VERSION 5.7 ;
  NOWIREEXTENSIONATPIN ON ;
  DIVIDERCHAR "/" ;
  BUSBITCHARS "[]" ;
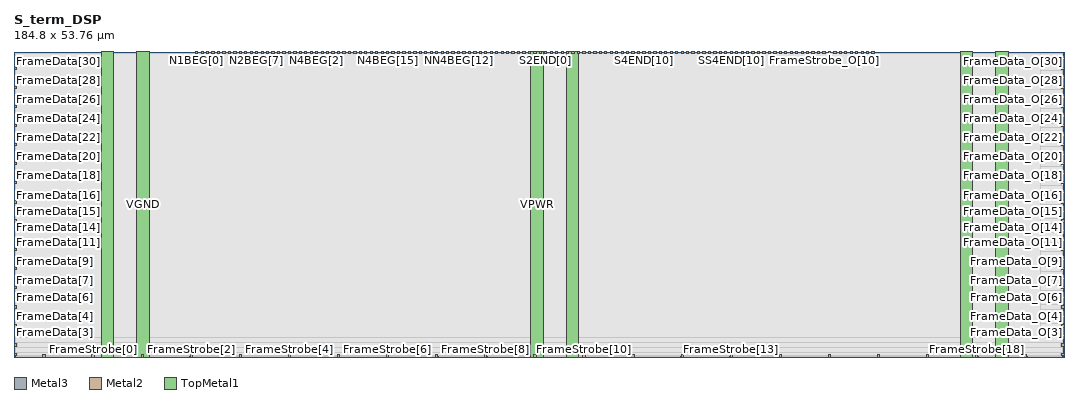
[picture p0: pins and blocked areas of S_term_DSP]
MACRO S_term_DSP
  CLASS BLOCK ;
  FOREIGN S_term_DSP ;
  ORIGIN 0.000 0.000 ;
  SIZE 184.800 BY 53.760 ;
  PIN FrameData[0]
    DIRECTION INPUT ;
    USE SIGNAL ;
    ANTENNAGATEAREA 0.180700 ;
    PORT
      LAYER Metal3 ;
        RECT 0.000 0.220 0.400 0.620 ;
    END
  END FrameData[0]
  PIN FrameData[10]
    DIRECTION INPUT ;
    USE SIGNAL ;
    ANTENNAGATEAREA 0.180700 ;
    PORT
      LAYER Metal3 ;
        RECT 0.000 17.020 0.400 17.420 ;
    END
  END FrameData[10]
  PIN FrameData[11]
    DIRECTION INPUT ;
    USE SIGNAL ;
    ANTENNAGATEAREA 0.180700 ;
    PORT
      LAYER Metal3 ;
        RECT 0.000 18.700 0.400 19.100 ;
    END
  END FrameData[11]
  PIN FrameData[12]
    DIRECTION INPUT ;
    USE SIGNAL ;
    ANTENNAGATEAREA 0.180700 ;
    PORT
      LAYER Metal3 ;
        RECT 0.000 20.380 0.400 20.780 ;
    END
  END FrameData[12]
  PIN FrameData[13]
    DIRECTION INPUT ;
    USE SIGNAL ;
    ANTENNAGATEAREA 0.180700 ;
    PORT
      LAYER Metal3 ;
        RECT 0.000 22.060 0.400 22.460 ;
    END
  END FrameData[13]
  PIN FrameData[14]
    DIRECTION INPUT ;
    USE SIGNAL ;
    ANTENNAGATEAREA 0.180700 ;
    PORT
      LAYER Metal3 ;
        RECT 0.000 23.740 0.400 24.140 ;
    END
  END FrameData[14]
  PIN FrameData[15]
    DIRECTION INPUT ;
    USE SIGNAL ;
    ANTENNAGATEAREA 0.180700 ;
    PORT
      LAYER Metal3 ;
        RECT 0.000 25.420 0.400 25.820 ;
    END
  END FrameData[15]
  PIN FrameData[16]
    DIRECTION INPUT ;
    USE SIGNAL ;
    ANTENNAGATEAREA 0.180700 ;
    PORT
      LAYER Metal3 ;
        RECT 0.000 27.100 0.400 27.500 ;
    END
  END FrameData[16]
  PIN FrameData[17]
    DIRECTION INPUT ;
    USE SIGNAL ;
    ANTENNAGATEAREA 0.180700 ;
    PORT
      LAYER Metal3 ;
        RECT 0.000 28.780 0.400 29.180 ;
    END
  END FrameData[17]
  PIN FrameData[18]
    DIRECTION INPUT ;
    USE SIGNAL ;
    ANTENNAGATEAREA 0.180700 ;
    PORT
      LAYER Metal3 ;
        RECT 0.000 30.460 0.400 30.860 ;
    END
  END FrameData[18]
  PIN FrameData[19]
    DIRECTION INPUT ;
    USE SIGNAL ;
    ANTENNAGATEAREA 0.180700 ;
    PORT
      LAYER Metal3 ;
        RECT 0.000 32.140 0.400 32.540 ;
    END
  END FrameData[19]
  PIN FrameData[1]
    DIRECTION INPUT ;
    USE SIGNAL ;
    ANTENNAGATEAREA 0.180700 ;
    PORT
      LAYER Metal3 ;
        RECT 0.000 1.900 0.400 2.300 ;
    END
  END FrameData[1]
  PIN FrameData[20]
    DIRECTION INPUT ;
    USE SIGNAL ;
    ANTENNAGATEAREA 0.180700 ;
    PORT
      LAYER Metal3 ;
        RECT 0.000 33.820 0.400 34.220 ;
    END
  END FrameData[20]
  PIN FrameData[21]
    DIRECTION INPUT ;
    USE SIGNAL ;
    ANTENNAGATEAREA 0.180700 ;
    PORT
      LAYER Metal3 ;
        RECT 0.000 35.500 0.400 35.900 ;
    END
  END FrameData[21]
  PIN FrameData[22]
    DIRECTION INPUT ;
    USE SIGNAL ;
    ANTENNAGATEAREA 0.180700 ;
    PORT
      LAYER Metal3 ;
        RECT 0.000 37.180 0.400 37.580 ;
    END
  END FrameData[22]
  PIN FrameData[23]
    DIRECTION INPUT ;
    USE SIGNAL ;
    ANTENNAGATEAREA 0.180700 ;
    PORT
      LAYER Metal3 ;
        RECT 0.000 38.860 0.400 39.260 ;
    END
  END FrameData[23]
  PIN FrameData[24]
    DIRECTION INPUT ;
    USE SIGNAL ;
    ANTENNAGATEAREA 0.180700 ;
    PORT
      LAYER Metal3 ;
        RECT 0.000 40.540 0.400 40.940 ;
    END
  END FrameData[24]
  PIN FrameData[25]
    DIRECTION INPUT ;
    USE SIGNAL ;
    ANTENNAGATEAREA 0.180700 ;
    PORT
      LAYER Metal3 ;
        RECT 0.000 42.220 0.400 42.620 ;
    END
  END FrameData[25]
  PIN FrameData[26]
    DIRECTION INPUT ;
    USE SIGNAL ;
    ANTENNAGATEAREA 0.180700 ;
    PORT
      LAYER Metal3 ;
        RECT 0.000 43.900 0.400 44.300 ;
    END
  END FrameData[26]
  PIN FrameData[27]
    DIRECTION INPUT ;
    USE SIGNAL ;
    ANTENNAGATEAREA 0.180700 ;
    PORT
      LAYER Metal3 ;
        RECT 0.000 45.580 0.400 45.980 ;
    END
  END FrameData[27]
  PIN FrameData[28]
    DIRECTION INPUT ;
    USE SIGNAL ;
    ANTENNAGATEAREA 0.180700 ;
    PORT
      LAYER Metal3 ;
        RECT 0.000 47.260 0.400 47.660 ;
    END
  END FrameData[28]
  PIN FrameData[29]
    DIRECTION INPUT ;
    USE SIGNAL ;
    ANTENNAGATEAREA 0.180700 ;
    PORT
      LAYER Metal3 ;
        RECT 0.000 48.940 0.400 49.340 ;
    END
  END FrameData[29]
  PIN FrameData[2]
    DIRECTION INPUT ;
    USE SIGNAL ;
    ANTENNAGATEAREA 0.180700 ;
    PORT
      LAYER Metal3 ;
        RECT 0.000 3.580 0.400 3.980 ;
    END
  END FrameData[2]
  PIN FrameData[30]
    DIRECTION INPUT ;
    USE SIGNAL ;
    ANTENNAGATEAREA 0.180700 ;
    PORT
      LAYER Metal3 ;
        RECT 0.000 50.620 0.400 51.020 ;
    END
  END FrameData[30]
  PIN FrameData[31]
    DIRECTION INPUT ;
    USE SIGNAL ;
    ANTENNAGATEAREA 0.180700 ;
    PORT
      LAYER Metal3 ;
        RECT 0.000 52.300 0.400 52.700 ;
    END
  END FrameData[31]
  PIN FrameData[3]
    DIRECTION INPUT ;
    USE SIGNAL ;
    ANTENNAGATEAREA 0.180700 ;
    PORT
      LAYER Metal3 ;
        RECT 0.000 5.260 0.400 5.660 ;
    END
  END FrameData[3]
  PIN FrameData[4]
    DIRECTION INPUT ;
    USE SIGNAL ;
    ANTENNAGATEAREA 0.180700 ;
    PORT
      LAYER Metal3 ;
        RECT 0.000 6.940 0.400 7.340 ;
    END
  END FrameData[4]
  PIN FrameData[5]
    DIRECTION INPUT ;
    USE SIGNAL ;
    ANTENNAGATEAREA 0.180700 ;
    PORT
      LAYER Metal3 ;
        RECT 0.000 8.620 0.400 9.020 ;
    END
  END FrameData[5]
  PIN FrameData[6]
    DIRECTION INPUT ;
    USE SIGNAL ;
    ANTENNAGATEAREA 0.180700 ;
    PORT
      LAYER Metal3 ;
        RECT 0.000 10.300 0.400 10.700 ;
    END
  END FrameData[6]
  PIN FrameData[7]
    DIRECTION INPUT ;
    USE SIGNAL ;
    ANTENNAGATEAREA 0.180700 ;
    PORT
      LAYER Metal3 ;
        RECT 0.000 11.980 0.400 12.380 ;
    END
  END FrameData[7]
  PIN FrameData[8]
    DIRECTION INPUT ;
    USE SIGNAL ;
    ANTENNAGATEAREA 0.180700 ;
    PORT
      LAYER Metal3 ;
        RECT 0.000 13.660 0.400 14.060 ;
    END
  END FrameData[8]
  PIN FrameData[9]
    DIRECTION INPUT ;
    USE SIGNAL ;
    ANTENNAGATEAREA 0.180700 ;
    PORT
      LAYER Metal3 ;
        RECT 0.000 15.340 0.400 15.740 ;
    END
  END FrameData[9]
  PIN FrameData_O[0]
    DIRECTION OUTPUT ;
    USE SIGNAL ;
    ANTENNADIFFAREA 0.708600 ;
    PORT
      LAYER Metal3 ;
        RECT 184.400 0.220 184.800 0.620 ;
    END
  END FrameData_O[0]
  PIN FrameData_O[10]
    DIRECTION OUTPUT ;
    USE SIGNAL ;
    ANTENNADIFFAREA 0.708600 ;
    PORT
      LAYER Metal3 ;
        RECT 184.400 17.020 184.800 17.420 ;
    END
  END FrameData_O[10]
  PIN FrameData_O[11]
    DIRECTION OUTPUT ;
    USE SIGNAL ;
    ANTENNADIFFAREA 0.708600 ;
    PORT
      LAYER Metal3 ;
        RECT 184.400 18.700 184.800 19.100 ;
    END
  END FrameData_O[11]
  PIN FrameData_O[12]
    DIRECTION OUTPUT ;
    USE SIGNAL ;
    ANTENNADIFFAREA 0.708600 ;
    PORT
      LAYER Metal3 ;
        RECT 184.400 20.380 184.800 20.780 ;
    END
  END FrameData_O[12]
  PIN FrameData_O[13]
    DIRECTION OUTPUT ;
    USE SIGNAL ;
    ANTENNADIFFAREA 0.708600 ;
    PORT
      LAYER Metal3 ;
        RECT 184.400 22.060 184.800 22.460 ;
    END
  END FrameData_O[13]
  PIN FrameData_O[14]
    DIRECTION OUTPUT ;
    USE SIGNAL ;
    ANTENNADIFFAREA 0.708600 ;
    PORT
      LAYER Metal3 ;
        RECT 184.400 23.740 184.800 24.140 ;
    END
  END FrameData_O[14]
  PIN FrameData_O[15]
    DIRECTION OUTPUT ;
    USE SIGNAL ;
    ANTENNADIFFAREA 0.708600 ;
    PORT
      LAYER Metal3 ;
        RECT 184.400 25.420 184.800 25.820 ;
    END
  END FrameData_O[15]
  PIN FrameData_O[16]
    DIRECTION OUTPUT ;
    USE SIGNAL ;
    ANTENNADIFFAREA 0.708600 ;
    PORT
      LAYER Metal3 ;
        RECT 184.400 27.100 184.800 27.500 ;
    END
  END FrameData_O[16]
  PIN FrameData_O[17]
    DIRECTION OUTPUT ;
    USE SIGNAL ;
    ANTENNADIFFAREA 0.708600 ;
    PORT
      LAYER Metal3 ;
        RECT 184.400 28.780 184.800 29.180 ;
    END
  END FrameData_O[17]
  PIN FrameData_O[18]
    DIRECTION OUTPUT ;
    USE SIGNAL ;
    ANTENNADIFFAREA 0.708600 ;
    PORT
      LAYER Metal3 ;
        RECT 184.400 30.460 184.800 30.860 ;
    END
  END FrameData_O[18]
  PIN FrameData_O[19]
    DIRECTION OUTPUT ;
    USE SIGNAL ;
    ANTENNADIFFAREA 0.708600 ;
    PORT
      LAYER Metal3 ;
        RECT 184.400 32.140 184.800 32.540 ;
    END
  END FrameData_O[19]
  PIN FrameData_O[1]
    DIRECTION OUTPUT ;
    USE SIGNAL ;
    ANTENNADIFFAREA 0.708600 ;
    PORT
      LAYER Metal3 ;
        RECT 184.400 1.900 184.800 2.300 ;
    END
  END FrameData_O[1]
  PIN FrameData_O[20]
    DIRECTION OUTPUT ;
    USE SIGNAL ;
    ANTENNADIFFAREA 0.708600 ;
    PORT
      LAYER Metal3 ;
        RECT 184.400 33.820 184.800 34.220 ;
    END
  END FrameData_O[20]
  PIN FrameData_O[21]
    DIRECTION OUTPUT ;
    USE SIGNAL ;
    ANTENNADIFFAREA 0.708600 ;
    PORT
      LAYER Metal3 ;
        RECT 184.400 35.500 184.800 35.900 ;
    END
  END FrameData_O[21]
  PIN FrameData_O[22]
    DIRECTION OUTPUT ;
    USE SIGNAL ;
    ANTENNADIFFAREA 0.708600 ;
    PORT
      LAYER Metal3 ;
        RECT 184.400 37.180 184.800 37.580 ;
    END
  END FrameData_O[22]
  PIN FrameData_O[23]
    DIRECTION OUTPUT ;
    USE SIGNAL ;
    ANTENNADIFFAREA 0.708600 ;
    PORT
      LAYER Metal3 ;
        RECT 184.400 38.860 184.800 39.260 ;
    END
  END FrameData_O[23]
  PIN FrameData_O[24]
    DIRECTION OUTPUT ;
    USE SIGNAL ;
    ANTENNADIFFAREA 0.708600 ;
    PORT
      LAYER Metal3 ;
        RECT 184.400 40.540 184.800 40.940 ;
    END
  END FrameData_O[24]
  PIN FrameData_O[25]
    DIRECTION OUTPUT ;
    USE SIGNAL ;
    ANTENNADIFFAREA 0.708600 ;
    PORT
      LAYER Metal3 ;
        RECT 184.400 42.220 184.800 42.620 ;
    END
  END FrameData_O[25]
  PIN FrameData_O[26]
    DIRECTION OUTPUT ;
    USE SIGNAL ;
    ANTENNADIFFAREA 0.708600 ;
    PORT
      LAYER Metal3 ;
        RECT 184.400 43.900 184.800 44.300 ;
    END
  END FrameData_O[26]
  PIN FrameData_O[27]
    DIRECTION OUTPUT ;
    USE SIGNAL ;
    ANTENNADIFFAREA 0.708600 ;
    PORT
      LAYER Metal3 ;
        RECT 184.400 45.580 184.800 45.980 ;
    END
  END FrameData_O[27]
  PIN FrameData_O[28]
    DIRECTION OUTPUT ;
    USE SIGNAL ;
    ANTENNADIFFAREA 0.708600 ;
    PORT
      LAYER Metal3 ;
        RECT 184.400 47.260 184.800 47.660 ;
    END
  END FrameData_O[28]
  PIN FrameData_O[29]
    DIRECTION OUTPUT ;
    USE SIGNAL ;
    ANTENNADIFFAREA 0.708600 ;
    PORT
      LAYER Metal3 ;
        RECT 184.400 48.940 184.800 49.340 ;
    END
  END FrameData_O[29]
  PIN FrameData_O[2]
    DIRECTION OUTPUT ;
    USE SIGNAL ;
    ANTENNADIFFAREA 0.708600 ;
    PORT
      LAYER Metal3 ;
        RECT 184.400 3.580 184.800 3.980 ;
    END
  END FrameData_O[2]
  PIN FrameData_O[30]
    DIRECTION OUTPUT ;
    USE SIGNAL ;
    ANTENNADIFFAREA 0.708600 ;
    PORT
      LAYER Metal3 ;
        RECT 184.400 50.620 184.800 51.020 ;
    END
  END FrameData_O[30]
  PIN FrameData_O[31]
    DIRECTION OUTPUT ;
    USE SIGNAL ;
    ANTENNADIFFAREA 0.708600 ;
    PORT
      LAYER Metal3 ;
        RECT 184.400 52.300 184.800 52.700 ;
    END
  END FrameData_O[31]
  PIN FrameData_O[3]
    DIRECTION OUTPUT ;
    USE SIGNAL ;
    ANTENNADIFFAREA 0.708600 ;
    PORT
      LAYER Metal3 ;
        RECT 184.400 5.260 184.800 5.660 ;
    END
  END FrameData_O[3]
  PIN FrameData_O[4]
    DIRECTION OUTPUT ;
    USE SIGNAL ;
    ANTENNADIFFAREA 0.708600 ;
    PORT
      LAYER Metal3 ;
        RECT 184.400 6.940 184.800 7.340 ;
    END
  END FrameData_O[4]
  PIN FrameData_O[5]
    DIRECTION OUTPUT ;
    USE SIGNAL ;
    ANTENNADIFFAREA 0.708600 ;
    PORT
      LAYER Metal3 ;
        RECT 184.400 8.620 184.800 9.020 ;
    END
  END FrameData_O[5]
  PIN FrameData_O[6]
    DIRECTION OUTPUT ;
    USE SIGNAL ;
    ANTENNADIFFAREA 0.708600 ;
    PORT
      LAYER Metal3 ;
        RECT 184.400 10.300 184.800 10.700 ;
    END
  END FrameData_O[6]
  PIN FrameData_O[7]
    DIRECTION OUTPUT ;
    USE SIGNAL ;
    ANTENNADIFFAREA 0.708600 ;
    PORT
      LAYER Metal3 ;
        RECT 184.400 11.980 184.800 12.380 ;
    END
  END FrameData_O[7]
  PIN FrameData_O[8]
    DIRECTION OUTPUT ;
    USE SIGNAL ;
    ANTENNADIFFAREA 0.708600 ;
    PORT
      LAYER Metal3 ;
        RECT 184.400 13.660 184.800 14.060 ;
    END
  END FrameData_O[8]
  PIN FrameData_O[9]
    DIRECTION OUTPUT ;
    USE SIGNAL ;
    ANTENNADIFFAREA 0.708600 ;
    PORT
      LAYER Metal3 ;
        RECT 184.400 15.340 184.800 15.740 ;
    END
  END FrameData_O[9]
  PIN FrameStrobe[0]
    DIRECTION INPUT ;
    USE SIGNAL ;
    ANTENNAGATEAREA 0.180700 ;
    PORT
      LAYER Metal2 ;
        RECT 13.720 0.000 14.120 0.400 ;
    END
  END FrameStrobe[0]
  PIN FrameStrobe[10]
    DIRECTION INPUT ;
    USE SIGNAL ;
    ANTENNAGATEAREA 0.180700 ;
    PORT
      LAYER Metal2 ;
        RECT 100.120 0.000 100.520 0.400 ;
    END
  END FrameStrobe[10]
  PIN FrameStrobe[11]
    DIRECTION INPUT ;
    USE SIGNAL ;
    ANTENNAGATEAREA 0.180700 ;
    PORT
      LAYER Metal2 ;
        RECT 108.760 0.000 109.160 0.400 ;
    END
  END FrameStrobe[11]
  PIN FrameStrobe[12]
    DIRECTION INPUT ;
    USE SIGNAL ;
    ANTENNAGATEAREA 0.180700 ;
    PORT
      LAYER Metal2 ;
        RECT 117.400 0.000 117.800 0.400 ;
    END
  END FrameStrobe[12]
  PIN FrameStrobe[13]
    DIRECTION INPUT ;
    USE SIGNAL ;
    ANTENNAGATEAREA 0.180700 ;
    PORT
      LAYER Metal2 ;
        RECT 126.040 0.000 126.440 0.400 ;
    END
  END FrameStrobe[13]
  PIN FrameStrobe[14]
    DIRECTION INPUT ;
    USE SIGNAL ;
    ANTENNAGATEAREA 0.180700 ;
    PORT
      LAYER Metal2 ;
        RECT 134.680 0.000 135.080 0.400 ;
    END
  END FrameStrobe[14]
  PIN FrameStrobe[15]
    DIRECTION INPUT ;
    USE SIGNAL ;
    ANTENNAGATEAREA 0.180700 ;
    PORT
      LAYER Metal2 ;
        RECT 143.320 0.000 143.720 0.400 ;
    END
  END FrameStrobe[15]
  PIN FrameStrobe[16]
    DIRECTION INPUT ;
    USE SIGNAL ;
    ANTENNAGATEAREA 0.180700 ;
    PORT
      LAYER Metal2 ;
        RECT 151.960 0.000 152.360 0.400 ;
    END
  END FrameStrobe[16]
  PIN FrameStrobe[17]
    DIRECTION INPUT ;
    USE SIGNAL ;
    ANTENNAGATEAREA 0.180700 ;
    PORT
      LAYER Metal2 ;
        RECT 160.600 0.000 161.000 0.400 ;
    END
  END FrameStrobe[17]
  PIN FrameStrobe[18]
    DIRECTION INPUT ;
    USE SIGNAL ;
    ANTENNAGATEAREA 0.180700 ;
    PORT
      LAYER Metal2 ;
        RECT 169.240 0.000 169.640 0.400 ;
    END
  END FrameStrobe[18]
  PIN FrameStrobe[19]
    DIRECTION INPUT ;
    USE SIGNAL ;
    ANTENNAGATEAREA 0.180700 ;
    PORT
      LAYER Metal2 ;
        RECT 177.880 0.000 178.280 0.400 ;
    END
  END FrameStrobe[19]
  PIN FrameStrobe[1]
    DIRECTION INPUT ;
    USE SIGNAL ;
    ANTENNAGATEAREA 0.180700 ;
    PORT
      LAYER Metal2 ;
        RECT 22.360 0.000 22.760 0.400 ;
    END
  END FrameStrobe[1]
  PIN FrameStrobe[2]
    DIRECTION INPUT ;
    USE SIGNAL ;
    ANTENNAGATEAREA 0.180700 ;
    PORT
      LAYER Metal2 ;
        RECT 31.000 0.000 31.400 0.400 ;
    END
  END FrameStrobe[2]
  PIN FrameStrobe[3]
    DIRECTION INPUT ;
    USE SIGNAL ;
    ANTENNAGATEAREA 0.180700 ;
    PORT
      LAYER Metal2 ;
        RECT 39.640 0.000 40.040 0.400 ;
    END
  END FrameStrobe[3]
  PIN FrameStrobe[4]
    DIRECTION INPUT ;
    USE SIGNAL ;
    ANTENNAGATEAREA 0.180700 ;
    PORT
      LAYER Metal2 ;
        RECT 48.280 0.000 48.680 0.400 ;
    END
  END FrameStrobe[4]
  PIN FrameStrobe[5]
    DIRECTION INPUT ;
    USE SIGNAL ;
    ANTENNAGATEAREA 0.180700 ;
    PORT
      LAYER Metal2 ;
        RECT 56.920 0.000 57.320 0.400 ;
    END
  END FrameStrobe[5]
  PIN FrameStrobe[6]
    DIRECTION INPUT ;
    USE SIGNAL ;
    ANTENNAGATEAREA 0.180700 ;
    PORT
      LAYER Metal2 ;
        RECT 65.560 0.000 65.960 0.400 ;
    END
  END FrameStrobe[6]
  PIN FrameStrobe[7]
    DIRECTION INPUT ;
    USE SIGNAL ;
    ANTENNAGATEAREA 0.180700 ;
    PORT
      LAYER Metal2 ;
        RECT 74.200 0.000 74.600 0.400 ;
    END
  END FrameStrobe[7]
  PIN FrameStrobe[8]
    DIRECTION INPUT ;
    USE SIGNAL ;
    ANTENNAGATEAREA 0.180700 ;
    PORT
      LAYER Metal2 ;
        RECT 82.840 0.000 83.240 0.400 ;
    END
  END FrameStrobe[8]
  PIN FrameStrobe[9]
    DIRECTION INPUT ;
    USE SIGNAL ;
    ANTENNAGATEAREA 0.180700 ;
    PORT
      LAYER Metal2 ;
        RECT 91.480 0.000 91.880 0.400 ;
    END
  END FrameStrobe[9]
  PIN FrameStrobe_O[0]
    DIRECTION OUTPUT ;
    USE SIGNAL ;
    ANTENNADIFFAREA 0.708600 ;
    PORT
      LAYER Metal2 ;
        RECT 132.760 53.360 133.160 53.760 ;
    END
  END FrameStrobe_O[0]
  PIN FrameStrobe_O[10]
    DIRECTION OUTPUT ;
    USE SIGNAL ;
    ANTENNADIFFAREA 0.708600 ;
    PORT
      LAYER Metal2 ;
        RECT 142.360 53.360 142.760 53.760 ;
    END
  END FrameStrobe_O[10]
  PIN FrameStrobe_O[11]
    DIRECTION OUTPUT ;
    USE SIGNAL ;
    ANTENNADIFFAREA 0.708600 ;
    PORT
      LAYER Metal2 ;
        RECT 143.320 53.360 143.720 53.760 ;
    END
  END FrameStrobe_O[11]
  PIN FrameStrobe_O[12]
    DIRECTION OUTPUT ;
    USE SIGNAL ;
    ANTENNADIFFAREA 0.708600 ;
    PORT
      LAYER Metal2 ;
        RECT 144.280 53.360 144.680 53.760 ;
    END
  END FrameStrobe_O[12]
  PIN FrameStrobe_O[13]
    DIRECTION OUTPUT ;
    USE SIGNAL ;
    ANTENNADIFFAREA 0.708600 ;
    PORT
      LAYER Metal2 ;
        RECT 145.240 53.360 145.640 53.760 ;
    END
  END FrameStrobe_O[13]
  PIN FrameStrobe_O[14]
    DIRECTION OUTPUT ;
    USE SIGNAL ;
    ANTENNADIFFAREA 0.708600 ;
    PORT
      LAYER Metal2 ;
        RECT 146.200 53.360 146.600 53.760 ;
    END
  END FrameStrobe_O[14]
  PIN FrameStrobe_O[15]
    DIRECTION OUTPUT ;
    USE SIGNAL ;
    ANTENNADIFFAREA 0.708600 ;
    PORT
      LAYER Metal2 ;
        RECT 147.160 53.360 147.560 53.760 ;
    END
  END FrameStrobe_O[15]
  PIN FrameStrobe_O[16]
    DIRECTION OUTPUT ;
    USE SIGNAL ;
    ANTENNADIFFAREA 0.708600 ;
    PORT
      LAYER Metal2 ;
        RECT 148.120 53.360 148.520 53.760 ;
    END
  END FrameStrobe_O[16]
  PIN FrameStrobe_O[17]
    DIRECTION OUTPUT ;
    USE SIGNAL ;
    ANTENNADIFFAREA 0.708600 ;
    PORT
      LAYER Metal2 ;
        RECT 149.080 53.360 149.480 53.760 ;
    END
  END FrameStrobe_O[17]
  PIN FrameStrobe_O[18]
    DIRECTION OUTPUT ;
    USE SIGNAL ;
    ANTENNADIFFAREA 0.708600 ;
    PORT
      LAYER Metal2 ;
        RECT 150.040 53.360 150.440 53.760 ;
    END
  END FrameStrobe_O[18]
  PIN FrameStrobe_O[19]
    DIRECTION OUTPUT ;
    USE SIGNAL ;
    ANTENNADIFFAREA 0.708600 ;
    PORT
      LAYER Metal2 ;
        RECT 151.000 53.360 151.400 53.760 ;
    END
  END FrameStrobe_O[19]
  PIN FrameStrobe_O[1]
    DIRECTION OUTPUT ;
    USE SIGNAL ;
    ANTENNADIFFAREA 0.708600 ;
    PORT
      LAYER Metal2 ;
        RECT 133.720 53.360 134.120 53.760 ;
    END
  END FrameStrobe_O[1]
  PIN FrameStrobe_O[2]
    DIRECTION OUTPUT ;
    USE SIGNAL ;
    ANTENNADIFFAREA 0.708600 ;
    PORT
      LAYER Metal2 ;
        RECT 134.680 53.360 135.080 53.760 ;
    END
  END FrameStrobe_O[2]
  PIN FrameStrobe_O[3]
    DIRECTION OUTPUT ;
    USE SIGNAL ;
    ANTENNADIFFAREA 0.708600 ;
    PORT
      LAYER Metal2 ;
        RECT 135.640 53.360 136.040 53.760 ;
    END
  END FrameStrobe_O[3]
  PIN FrameStrobe_O[4]
    DIRECTION OUTPUT ;
    USE SIGNAL ;
    ANTENNADIFFAREA 0.708600 ;
    PORT
      LAYER Metal2 ;
        RECT 136.600 53.360 137.000 53.760 ;
    END
  END FrameStrobe_O[4]
  PIN FrameStrobe_O[5]
    DIRECTION OUTPUT ;
    USE SIGNAL ;
    ANTENNADIFFAREA 0.708600 ;
    PORT
      LAYER Metal2 ;
        RECT 137.560 53.360 137.960 53.760 ;
    END
  END FrameStrobe_O[5]
  PIN FrameStrobe_O[6]
    DIRECTION OUTPUT ;
    USE SIGNAL ;
    ANTENNADIFFAREA 0.708600 ;
    PORT
      LAYER Metal2 ;
        RECT 138.520 53.360 138.920 53.760 ;
    END
  END FrameStrobe_O[6]
  PIN FrameStrobe_O[7]
    DIRECTION OUTPUT ;
    USE SIGNAL ;
    ANTENNADIFFAREA 0.708600 ;
    PORT
      LAYER Metal2 ;
        RECT 139.480 53.360 139.880 53.760 ;
    END
  END FrameStrobe_O[7]
  PIN FrameStrobe_O[8]
    DIRECTION OUTPUT ;
    USE SIGNAL ;
    ANTENNADIFFAREA 0.708600 ;
    PORT
      LAYER Metal2 ;
        RECT 140.440 53.360 140.840 53.760 ;
    END
  END FrameStrobe_O[8]
  PIN FrameStrobe_O[9]
    DIRECTION OUTPUT ;
    USE SIGNAL ;
    ANTENNADIFFAREA 0.708600 ;
    PORT
      LAYER Metal2 ;
        RECT 141.400 53.360 141.800 53.760 ;
    END
  END FrameStrobe_O[9]
  PIN N1BEG[0]
    DIRECTION OUTPUT ;
    USE SIGNAL ;
    ANTENNADIFFAREA 0.708600 ;
    PORT
      LAYER Metal2 ;
        RECT 31.960 53.360 32.360 53.760 ;
    END
  END N1BEG[0]
  PIN N1BEG[1]
    DIRECTION OUTPUT ;
    USE SIGNAL ;
    ANTENNADIFFAREA 0.708600 ;
    PORT
      LAYER Metal2 ;
        RECT 32.920 53.360 33.320 53.760 ;
    END
  END N1BEG[1]
  PIN N1BEG[2]
    DIRECTION OUTPUT ;
    USE SIGNAL ;
    ANTENNADIFFAREA 0.708600 ;
    PORT
      LAYER Metal2 ;
        RECT 33.880 53.360 34.280 53.760 ;
    END
  END N1BEG[2]
  PIN N1BEG[3]
    DIRECTION OUTPUT ;
    USE SIGNAL ;
    ANTENNADIFFAREA 0.708600 ;
    PORT
      LAYER Metal2 ;
        RECT 34.840 53.360 35.240 53.760 ;
    END
  END N1BEG[3]
  PIN N2BEG[0]
    DIRECTION OUTPUT ;
    USE SIGNAL ;
    ANTENNADIFFAREA 0.708600 ;
    PORT
      LAYER Metal2 ;
        RECT 35.800 53.360 36.200 53.760 ;
    END
  END N2BEG[0]
  PIN N2BEG[1]
    DIRECTION OUTPUT ;
    USE SIGNAL ;
    ANTENNADIFFAREA 0.708600 ;
    PORT
      LAYER Metal2 ;
        RECT 36.760 53.360 37.160 53.760 ;
    END
  END N2BEG[1]
  PIN N2BEG[2]
    DIRECTION OUTPUT ;
    USE SIGNAL ;
    ANTENNADIFFAREA 0.708600 ;
    PORT
      LAYER Metal2 ;
        RECT 37.720 53.360 38.120 53.760 ;
    END
  END N2BEG[2]
  PIN N2BEG[3]
    DIRECTION OUTPUT ;
    USE SIGNAL ;
    ANTENNADIFFAREA 0.708600 ;
    PORT
      LAYER Metal2 ;
        RECT 38.680 53.360 39.080 53.760 ;
    END
  END N2BEG[3]
  PIN N2BEG[4]
    DIRECTION OUTPUT ;
    USE SIGNAL ;
    ANTENNADIFFAREA 0.708600 ;
    PORT
      LAYER Metal2 ;
        RECT 39.640 53.360 40.040 53.760 ;
    END
  END N2BEG[4]
  PIN N2BEG[5]
    DIRECTION OUTPUT ;
    USE SIGNAL ;
    ANTENNADIFFAREA 0.708600 ;
    PORT
      LAYER Metal2 ;
        RECT 40.600 53.360 41.000 53.760 ;
    END
  END N2BEG[5]
  PIN N2BEG[6]
    DIRECTION OUTPUT ;
    USE SIGNAL ;
    ANTENNADIFFAREA 0.708600 ;
    PORT
      LAYER Metal2 ;
        RECT 41.560 53.360 41.960 53.760 ;
    END
  END N2BEG[6]
  PIN N2BEG[7]
    DIRECTION OUTPUT ;
    USE SIGNAL ;
    ANTENNADIFFAREA 0.708600 ;
    PORT
      LAYER Metal2 ;
        RECT 42.520 53.360 42.920 53.760 ;
    END
  END N2BEG[7]
  PIN N2BEGb[0]
    DIRECTION OUTPUT ;
    USE SIGNAL ;
    ANTENNADIFFAREA 0.708600 ;
    PORT
      LAYER Metal2 ;
        RECT 43.480 53.360 43.880 53.760 ;
    END
  END N2BEGb[0]
  PIN N2BEGb[1]
    DIRECTION OUTPUT ;
    USE SIGNAL ;
    ANTENNADIFFAREA 0.708600 ;
    PORT
      LAYER Metal2 ;
        RECT 44.440 53.360 44.840 53.760 ;
    END
  END N2BEGb[1]
  PIN N2BEGb[2]
    DIRECTION OUTPUT ;
    USE SIGNAL ;
    ANTENNADIFFAREA 0.708600 ;
    PORT
      LAYER Metal2 ;
        RECT 45.400 53.360 45.800 53.760 ;
    END
  END N2BEGb[2]
  PIN N2BEGb[3]
    DIRECTION OUTPUT ;
    USE SIGNAL ;
    ANTENNADIFFAREA 0.708600 ;
    PORT
      LAYER Metal2 ;
        RECT 46.360 53.360 46.760 53.760 ;
    END
  END N2BEGb[3]
  PIN N2BEGb[4]
    DIRECTION OUTPUT ;
    USE SIGNAL ;
    ANTENNADIFFAREA 0.708600 ;
    PORT
      LAYER Metal2 ;
        RECT 47.320 53.360 47.720 53.760 ;
    END
  END N2BEGb[4]
  PIN N2BEGb[5]
    DIRECTION OUTPUT ;
    USE SIGNAL ;
    ANTENNADIFFAREA 0.708600 ;
    PORT
      LAYER Metal2 ;
        RECT 48.280 53.360 48.680 53.760 ;
    END
  END N2BEGb[5]
  PIN N2BEGb[6]
    DIRECTION OUTPUT ;
    USE SIGNAL ;
    ANTENNADIFFAREA 0.708600 ;
    PORT
      LAYER Metal2 ;
        RECT 49.240 53.360 49.640 53.760 ;
    END
  END N2BEGb[6]
  PIN N2BEGb[7]
    DIRECTION OUTPUT ;
    USE SIGNAL ;
    ANTENNADIFFAREA 0.708600 ;
    PORT
      LAYER Metal2 ;
        RECT 50.200 53.360 50.600 53.760 ;
    END
  END N2BEGb[7]
  PIN N4BEG[0]
    DIRECTION OUTPUT ;
    USE SIGNAL ;
    ANTENNADIFFAREA 0.708600 ;
    PORT
      LAYER Metal2 ;
        RECT 51.160 53.360 51.560 53.760 ;
    END
  END N4BEG[0]
  PIN N4BEG[10]
    DIRECTION OUTPUT ;
    USE SIGNAL ;
    ANTENNADIFFAREA 0.708600 ;
    PORT
      LAYER Metal2 ;
        RECT 60.760 53.360 61.160 53.760 ;
    END
  END N4BEG[10]
  PIN N4BEG[11]
    DIRECTION OUTPUT ;
    USE SIGNAL ;
    ANTENNADIFFAREA 0.708600 ;
    PORT
      LAYER Metal2 ;
        RECT 61.720 53.360 62.120 53.760 ;
    END
  END N4BEG[11]
  PIN N4BEG[12]
    DIRECTION OUTPUT ;
    USE SIGNAL ;
    ANTENNADIFFAREA 0.708600 ;
    PORT
      LAYER Metal2 ;
        RECT 62.680 53.360 63.080 53.760 ;
    END
  END N4BEG[12]
  PIN N4BEG[13]
    DIRECTION OUTPUT ;
    USE SIGNAL ;
    ANTENNADIFFAREA 0.708600 ;
    PORT
      LAYER Metal2 ;
        RECT 63.640 53.360 64.040 53.760 ;
    END
  END N4BEG[13]
  PIN N4BEG[14]
    DIRECTION OUTPUT ;
    USE SIGNAL ;
    ANTENNADIFFAREA 0.708600 ;
    PORT
      LAYER Metal2 ;
        RECT 64.600 53.360 65.000 53.760 ;
    END
  END N4BEG[14]
  PIN N4BEG[15]
    DIRECTION OUTPUT ;
    USE SIGNAL ;
    ANTENNADIFFAREA 0.708600 ;
    PORT
      LAYER Metal2 ;
        RECT 65.560 53.360 65.960 53.760 ;
    END
  END N4BEG[15]
  PIN N4BEG[1]
    DIRECTION OUTPUT ;
    USE SIGNAL ;
    ANTENNADIFFAREA 0.708600 ;
    PORT
      LAYER Metal2 ;
        RECT 52.120 53.360 52.520 53.760 ;
    END
  END N4BEG[1]
  PIN N4BEG[2]
    DIRECTION OUTPUT ;
    USE SIGNAL ;
    ANTENNADIFFAREA 0.708600 ;
    PORT
      LAYER Metal2 ;
        RECT 53.080 53.360 53.480 53.760 ;
    END
  END N4BEG[2]
  PIN N4BEG[3]
    DIRECTION OUTPUT ;
    USE SIGNAL ;
    ANTENNADIFFAREA 0.708600 ;
    PORT
      LAYER Metal2 ;
        RECT 54.040 53.360 54.440 53.760 ;
    END
  END N4BEG[3]
  PIN N4BEG[4]
    DIRECTION OUTPUT ;
    USE SIGNAL ;
    ANTENNADIFFAREA 0.708600 ;
    PORT
      LAYER Metal2 ;
        RECT 55.000 53.360 55.400 53.760 ;
    END
  END N4BEG[4]
  PIN N4BEG[5]
    DIRECTION OUTPUT ;
    USE SIGNAL ;
    ANTENNADIFFAREA 0.708600 ;
    PORT
      LAYER Metal2 ;
        RECT 55.960 53.360 56.360 53.760 ;
    END
  END N4BEG[5]
  PIN N4BEG[6]
    DIRECTION OUTPUT ;
    USE SIGNAL ;
    ANTENNADIFFAREA 0.708600 ;
    PORT
      LAYER Metal2 ;
        RECT 56.920 53.360 57.320 53.760 ;
    END
  END N4BEG[6]
  PIN N4BEG[7]
    DIRECTION OUTPUT ;
    USE SIGNAL ;
    ANTENNADIFFAREA 0.708600 ;
    PORT
      LAYER Metal2 ;
        RECT 57.880 53.360 58.280 53.760 ;
    END
  END N4BEG[7]
  PIN N4BEG[8]
    DIRECTION OUTPUT ;
    USE SIGNAL ;
    ANTENNADIFFAREA 0.708600 ;
    PORT
      LAYER Metal2 ;
        RECT 58.840 53.360 59.240 53.760 ;
    END
  END N4BEG[8]
  PIN N4BEG[9]
    DIRECTION OUTPUT ;
    USE SIGNAL ;
    ANTENNADIFFAREA 0.708600 ;
    PORT
      LAYER Metal2 ;
        RECT 59.800 53.360 60.200 53.760 ;
    END
  END N4BEG[9]
  PIN NN4BEG[0]
    DIRECTION OUTPUT ;
    USE SIGNAL ;
    ANTENNADIFFAREA 0.708600 ;
    PORT
      LAYER Metal2 ;
        RECT 66.520 53.360 66.920 53.760 ;
    END
  END NN4BEG[0]
  PIN NN4BEG[10]
    DIRECTION OUTPUT ;
    USE SIGNAL ;
    ANTENNADIFFAREA 0.708600 ;
    PORT
      LAYER Metal2 ;
        RECT 76.120 53.360 76.520 53.760 ;
    END
  END NN4BEG[10]
  PIN NN4BEG[11]
    DIRECTION OUTPUT ;
    USE SIGNAL ;
    ANTENNADIFFAREA 0.708600 ;
    PORT
      LAYER Metal2 ;
        RECT 77.080 53.360 77.480 53.760 ;
    END
  END NN4BEG[11]
  PIN NN4BEG[12]
    DIRECTION OUTPUT ;
    USE SIGNAL ;
    ANTENNADIFFAREA 0.708600 ;
    PORT
      LAYER Metal2 ;
        RECT 78.040 53.360 78.440 53.760 ;
    END
  END NN4BEG[12]
  PIN NN4BEG[13]
    DIRECTION OUTPUT ;
    USE SIGNAL ;
    ANTENNADIFFAREA 0.708600 ;
    PORT
      LAYER Metal2 ;
        RECT 79.000 53.360 79.400 53.760 ;
    END
  END NN4BEG[13]
  PIN NN4BEG[14]
    DIRECTION OUTPUT ;
    USE SIGNAL ;
    ANTENNADIFFAREA 0.708600 ;
    PORT
      LAYER Metal2 ;
        RECT 79.960 53.360 80.360 53.760 ;
    END
  END NN4BEG[14]
  PIN NN4BEG[15]
    DIRECTION OUTPUT ;
    USE SIGNAL ;
    ANTENNADIFFAREA 0.708600 ;
    PORT
      LAYER Metal2 ;
        RECT 80.920 53.360 81.320 53.760 ;
    END
  END NN4BEG[15]
  PIN NN4BEG[1]
    DIRECTION OUTPUT ;
    USE SIGNAL ;
    ANTENNADIFFAREA 0.708600 ;
    PORT
      LAYER Metal2 ;
        RECT 67.480 53.360 67.880 53.760 ;
    END
  END NN4BEG[1]
  PIN NN4BEG[2]
    DIRECTION OUTPUT ;
    USE SIGNAL ;
    ANTENNADIFFAREA 0.708600 ;
    PORT
      LAYER Metal2 ;
        RECT 68.440 53.360 68.840 53.760 ;
    END
  END NN4BEG[2]
  PIN NN4BEG[3]
    DIRECTION OUTPUT ;
    USE SIGNAL ;
    ANTENNADIFFAREA 0.708600 ;
    PORT
      LAYER Metal2 ;
        RECT 69.400 53.360 69.800 53.760 ;
    END
  END NN4BEG[3]
  PIN NN4BEG[4]
    DIRECTION OUTPUT ;
    USE SIGNAL ;
    ANTENNADIFFAREA 0.708600 ;
    PORT
      LAYER Metal2 ;
        RECT 70.360 53.360 70.760 53.760 ;
    END
  END NN4BEG[4]
  PIN NN4BEG[5]
    DIRECTION OUTPUT ;
    USE SIGNAL ;
    ANTENNADIFFAREA 0.708600 ;
    PORT
      LAYER Metal2 ;
        RECT 71.320 53.360 71.720 53.760 ;
    END
  END NN4BEG[5]
  PIN NN4BEG[6]
    DIRECTION OUTPUT ;
    USE SIGNAL ;
    ANTENNADIFFAREA 0.708600 ;
    PORT
      LAYER Metal2 ;
        RECT 72.280 53.360 72.680 53.760 ;
    END
  END NN4BEG[6]
  PIN NN4BEG[7]
    DIRECTION OUTPUT ;
    USE SIGNAL ;
    ANTENNADIFFAREA 0.708600 ;
    PORT
      LAYER Metal2 ;
        RECT 73.240 53.360 73.640 53.760 ;
    END
  END NN4BEG[7]
  PIN NN4BEG[8]
    DIRECTION OUTPUT ;
    USE SIGNAL ;
    ANTENNADIFFAREA 0.708600 ;
    PORT
      LAYER Metal2 ;
        RECT 74.200 53.360 74.600 53.760 ;
    END
  END NN4BEG[8]
  PIN NN4BEG[9]
    DIRECTION OUTPUT ;
    USE SIGNAL ;
    ANTENNADIFFAREA 0.708600 ;
    PORT
      LAYER Metal2 ;
        RECT 75.160 53.360 75.560 53.760 ;
    END
  END NN4BEG[9]
  PIN S1END[0]
    DIRECTION INPUT ;
    USE SIGNAL ;
    ANTENNAGATEAREA 0.180700 ;
    PORT
      LAYER Metal2 ;
        RECT 81.880 53.360 82.280 53.760 ;
    END
  END S1END[0]
  PIN S1END[1]
    DIRECTION INPUT ;
    USE SIGNAL ;
    ANTENNAGATEAREA 0.180700 ;
    PORT
      LAYER Metal2 ;
        RECT 82.840 53.360 83.240 53.760 ;
    END
  END S1END[1]
  PIN S1END[2]
    DIRECTION INPUT ;
    USE SIGNAL ;
    ANTENNAGATEAREA 0.180700 ;
    PORT
      LAYER Metal2 ;
        RECT 83.800 53.360 84.200 53.760 ;
    END
  END S1END[2]
  PIN S1END[3]
    DIRECTION INPUT ;
    USE SIGNAL ;
    ANTENNAGATEAREA 0.180700 ;
    PORT
      LAYER Metal2 ;
        RECT 84.760 53.360 85.160 53.760 ;
    END
  END S1END[3]
  PIN S2END[0]
    DIRECTION INPUT ;
    USE SIGNAL ;
    ANTENNAGATEAREA 0.180700 ;
    PORT
      LAYER Metal2 ;
        RECT 93.400 53.360 93.800 53.760 ;
    END
  END S2END[0]
  PIN S2END[1]
    DIRECTION INPUT ;
    USE SIGNAL ;
    ANTENNAGATEAREA 0.180700 ;
    PORT
      LAYER Metal2 ;
        RECT 94.360 53.360 94.760 53.760 ;
    END
  END S2END[1]
  PIN S2END[2]
    DIRECTION INPUT ;
    USE SIGNAL ;
    ANTENNAGATEAREA 0.180700 ;
    PORT
      LAYER Metal2 ;
        RECT 95.320 53.360 95.720 53.760 ;
    END
  END S2END[2]
  PIN S2END[3]
    DIRECTION INPUT ;
    USE SIGNAL ;
    ANTENNAGATEAREA 0.180700 ;
    PORT
      LAYER Metal2 ;
        RECT 96.280 53.360 96.680 53.760 ;
    END
  END S2END[3]
  PIN S2END[4]
    DIRECTION INPUT ;
    USE SIGNAL ;
    ANTENNAGATEAREA 0.180700 ;
    PORT
      LAYER Metal2 ;
        RECT 97.240 53.360 97.640 53.760 ;
    END
  END S2END[4]
  PIN S2END[5]
    DIRECTION INPUT ;
    USE SIGNAL ;
    ANTENNAGATEAREA 0.180700 ;
    PORT
      LAYER Metal2 ;
        RECT 98.200 53.360 98.600 53.760 ;
    END
  END S2END[5]
  PIN S2END[6]
    DIRECTION INPUT ;
    USE SIGNAL ;
    ANTENNAGATEAREA 0.180700 ;
    PORT
      LAYER Metal2 ;
        RECT 99.160 53.360 99.560 53.760 ;
    END
  END S2END[6]
  PIN S2END[7]
    DIRECTION INPUT ;
    USE SIGNAL ;
    ANTENNAGATEAREA 0.180700 ;
    PORT
      LAYER Metal2 ;
        RECT 100.120 53.360 100.520 53.760 ;
    END
  END S2END[7]
  PIN S2MID[0]
    DIRECTION INPUT ;
    USE SIGNAL ;
    ANTENNAGATEAREA 0.180700 ;
    PORT
      LAYER Metal2 ;
        RECT 85.720 53.360 86.120 53.760 ;
    END
  END S2MID[0]
  PIN S2MID[1]
    DIRECTION INPUT ;
    USE SIGNAL ;
    ANTENNAGATEAREA 0.180700 ;
    PORT
      LAYER Metal2 ;
        RECT 86.680 53.360 87.080 53.760 ;
    END
  END S2MID[1]
  PIN S2MID[2]
    DIRECTION INPUT ;
    USE SIGNAL ;
    ANTENNAGATEAREA 0.180700 ;
    PORT
      LAYER Metal2 ;
        RECT 87.640 53.360 88.040 53.760 ;
    END
  END S2MID[2]
  PIN S2MID[3]
    DIRECTION INPUT ;
    USE SIGNAL ;
    ANTENNAGATEAREA 0.180700 ;
    PORT
      LAYER Metal2 ;
        RECT 88.600 53.360 89.000 53.760 ;
    END
  END S2MID[3]
  PIN S2MID[4]
    DIRECTION INPUT ;
    USE SIGNAL ;
    ANTENNAGATEAREA 0.180700 ;
    PORT
      LAYER Metal2 ;
        RECT 89.560 53.360 89.960 53.760 ;
    END
  END S2MID[4]
  PIN S2MID[5]
    DIRECTION INPUT ;
    USE SIGNAL ;
    ANTENNAGATEAREA 0.180700 ;
    PORT
      LAYER Metal2 ;
        RECT 90.520 53.360 90.920 53.760 ;
    END
  END S2MID[5]
  PIN S2MID[6]
    DIRECTION INPUT ;
    USE SIGNAL ;
    ANTENNAGATEAREA 0.180700 ;
    PORT
      LAYER Metal2 ;
        RECT 91.480 53.360 91.880 53.760 ;
    END
  END S2MID[6]
  PIN S2MID[7]
    DIRECTION INPUT ;
    USE SIGNAL ;
    ANTENNAGATEAREA 0.180700 ;
    PORT
      LAYER Metal2 ;
        RECT 92.440 53.360 92.840 53.760 ;
    END
  END S2MID[7]
  PIN S4END[0]
    DIRECTION INPUT ;
    USE SIGNAL ;
    ANTENNAGATEAREA 0.180700 ;
    PORT
      LAYER Metal2 ;
        RECT 101.080 53.360 101.480 53.760 ;
    END
  END S4END[0]
  PIN S4END[10]
    DIRECTION INPUT ;
    USE SIGNAL ;
    ANTENNAGATEAREA 0.180700 ;
    PORT
      LAYER Metal2 ;
        RECT 110.680 53.360 111.080 53.760 ;
    END
  END S4END[10]
  PIN S4END[11]
    DIRECTION INPUT ;
    USE SIGNAL ;
    ANTENNAGATEAREA 0.180700 ;
    PORT
      LAYER Metal2 ;
        RECT 111.640 53.360 112.040 53.760 ;
    END
  END S4END[11]
  PIN S4END[12]
    DIRECTION INPUT ;
    USE SIGNAL ;
    ANTENNAGATEAREA 0.180700 ;
    PORT
      LAYER Metal2 ;
        RECT 112.600 53.360 113.000 53.760 ;
    END
  END S4END[12]
  PIN S4END[13]
    DIRECTION INPUT ;
    USE SIGNAL ;
    ANTENNAGATEAREA 0.180700 ;
    PORT
      LAYER Metal2 ;
        RECT 113.560 53.360 113.960 53.760 ;
    END
  END S4END[13]
  PIN S4END[14]
    DIRECTION INPUT ;
    USE SIGNAL ;
    ANTENNAGATEAREA 0.180700 ;
    PORT
      LAYER Metal2 ;
        RECT 114.520 53.360 114.920 53.760 ;
    END
  END S4END[14]
  PIN S4END[15]
    DIRECTION INPUT ;
    USE SIGNAL ;
    ANTENNAGATEAREA 0.180700 ;
    PORT
      LAYER Metal2 ;
        RECT 115.480 53.360 115.880 53.760 ;
    END
  END S4END[15]
  PIN S4END[1]
    DIRECTION INPUT ;
    USE SIGNAL ;
    ANTENNAGATEAREA 0.180700 ;
    PORT
      LAYER Metal2 ;
        RECT 102.040 53.360 102.440 53.760 ;
    END
  END S4END[1]
  PIN S4END[2]
    DIRECTION INPUT ;
    USE SIGNAL ;
    ANTENNAGATEAREA 0.180700 ;
    PORT
      LAYER Metal2 ;
        RECT 103.000 53.360 103.400 53.760 ;
    END
  END S4END[2]
  PIN S4END[3]
    DIRECTION INPUT ;
    USE SIGNAL ;
    ANTENNAGATEAREA 0.180700 ;
    PORT
      LAYER Metal2 ;
        RECT 103.960 53.360 104.360 53.760 ;
    END
  END S4END[3]
  PIN S4END[4]
    DIRECTION INPUT ;
    USE SIGNAL ;
    ANTENNAGATEAREA 0.180700 ;
    PORT
      LAYER Metal2 ;
        RECT 104.920 53.360 105.320 53.760 ;
    END
  END S4END[4]
  PIN S4END[5]
    DIRECTION INPUT ;
    USE SIGNAL ;
    ANTENNAGATEAREA 0.180700 ;
    PORT
      LAYER Metal2 ;
        RECT 105.880 53.360 106.280 53.760 ;
    END
  END S4END[5]
  PIN S4END[6]
    DIRECTION INPUT ;
    USE SIGNAL ;
    ANTENNAGATEAREA 0.180700 ;
    PORT
      LAYER Metal2 ;
        RECT 106.840 53.360 107.240 53.760 ;
    END
  END S4END[6]
  PIN S4END[7]
    DIRECTION INPUT ;
    USE SIGNAL ;
    ANTENNAGATEAREA 0.180700 ;
    PORT
      LAYER Metal2 ;
        RECT 107.800 53.360 108.200 53.760 ;
    END
  END S4END[7]
  PIN S4END[8]
    DIRECTION INPUT ;
    USE SIGNAL ;
    ANTENNAGATEAREA 0.180700 ;
    PORT
      LAYER Metal2 ;
        RECT 108.760 53.360 109.160 53.760 ;
    END
  END S4END[8]
  PIN S4END[9]
    DIRECTION INPUT ;
    USE SIGNAL ;
    ANTENNAGATEAREA 0.180700 ;
    PORT
      LAYER Metal2 ;
        RECT 109.720 53.360 110.120 53.760 ;
    END
  END S4END[9]
  PIN SS4END[0]
    DIRECTION INPUT ;
    USE SIGNAL ;
    ANTENNAGATEAREA 0.180700 ;
    PORT
      LAYER Metal2 ;
        RECT 116.440 53.360 116.840 53.760 ;
    END
  END SS4END[0]
  PIN SS4END[10]
    DIRECTION INPUT ;
    USE SIGNAL ;
    ANTENNAGATEAREA 0.180700 ;
    PORT
      LAYER Metal2 ;
        RECT 126.040 53.360 126.440 53.760 ;
    END
  END SS4END[10]
  PIN SS4END[11]
    DIRECTION INPUT ;
    USE SIGNAL ;
    ANTENNAGATEAREA 0.180700 ;
    PORT
      LAYER Metal2 ;
        RECT 127.000 53.360 127.400 53.760 ;
    END
  END SS4END[11]
  PIN SS4END[12]
    DIRECTION INPUT ;
    USE SIGNAL ;
    ANTENNAGATEAREA 0.180700 ;
    PORT
      LAYER Metal2 ;
        RECT 127.960 53.360 128.360 53.760 ;
    END
  END SS4END[12]
  PIN SS4END[13]
    DIRECTION INPUT ;
    USE SIGNAL ;
    ANTENNAGATEAREA 0.180700 ;
    PORT
      LAYER Metal2 ;
        RECT 128.920 53.360 129.320 53.760 ;
    END
  END SS4END[13]
  PIN SS4END[14]
    DIRECTION INPUT ;
    USE SIGNAL ;
    ANTENNAGATEAREA 0.180700 ;
    PORT
      LAYER Metal2 ;
        RECT 129.880 53.360 130.280 53.760 ;
    END
  END SS4END[14]
  PIN SS4END[15]
    DIRECTION INPUT ;
    USE SIGNAL ;
    ANTENNAGATEAREA 0.180700 ;
    PORT
      LAYER Metal2 ;
        RECT 130.840 53.360 131.240 53.760 ;
    END
  END SS4END[15]
  PIN SS4END[1]
    DIRECTION INPUT ;
    USE SIGNAL ;
    ANTENNAGATEAREA 0.180700 ;
    PORT
      LAYER Metal2 ;
        RECT 117.400 53.360 117.800 53.760 ;
    END
  END SS4END[1]
  PIN SS4END[2]
    DIRECTION INPUT ;
    USE SIGNAL ;
    ANTENNAGATEAREA 0.180700 ;
    PORT
      LAYER Metal2 ;
        RECT 118.360 53.360 118.760 53.760 ;
    END
  END SS4END[2]
  PIN SS4END[3]
    DIRECTION INPUT ;
    USE SIGNAL ;
    ANTENNAGATEAREA 0.180700 ;
    PORT
      LAYER Metal2 ;
        RECT 119.320 53.360 119.720 53.760 ;
    END
  END SS4END[3]
  PIN SS4END[4]
    DIRECTION INPUT ;
    USE SIGNAL ;
    ANTENNAGATEAREA 0.180700 ;
    PORT
      LAYER Metal2 ;
        RECT 120.280 53.360 120.680 53.760 ;
    END
  END SS4END[4]
  PIN SS4END[5]
    DIRECTION INPUT ;
    USE SIGNAL ;
    ANTENNAGATEAREA 0.180700 ;
    PORT
      LAYER Metal2 ;
        RECT 121.240 53.360 121.640 53.760 ;
    END
  END SS4END[5]
  PIN SS4END[6]
    DIRECTION INPUT ;
    USE SIGNAL ;
    ANTENNAGATEAREA 0.180700 ;
    PORT
      LAYER Metal2 ;
        RECT 122.200 53.360 122.600 53.760 ;
    END
  END SS4END[6]
  PIN SS4END[7]
    DIRECTION INPUT ;
    USE SIGNAL ;
    ANTENNAGATEAREA 0.180700 ;
    PORT
      LAYER Metal2 ;
        RECT 123.160 53.360 123.560 53.760 ;
    END
  END SS4END[7]
  PIN SS4END[8]
    DIRECTION INPUT ;
    USE SIGNAL ;
    ANTENNAGATEAREA 0.180700 ;
    PORT
      LAYER Metal2 ;
        RECT 124.120 53.360 124.520 53.760 ;
    END
  END SS4END[8]
  PIN SS4END[9]
    DIRECTION INPUT ;
    USE SIGNAL ;
    ANTENNAGATEAREA 0.180700 ;
    PORT
      LAYER Metal2 ;
        RECT 125.080 53.360 125.480 53.760 ;
    END
  END SS4END[9]
  PIN UserCLK
    DIRECTION INPUT ;
    USE SIGNAL ;
    ANTENNAGATEAREA 0.180700 ;
    PORT
      LAYER Metal2 ;
        RECT 5.080 0.000 5.480 0.400 ;
    END
  END UserCLK
  PIN UserCLKo
    DIRECTION OUTPUT ;
    USE SIGNAL ;
    ANTENNADIFFAREA 0.708600 ;
    PORT
      LAYER Metal2 ;
        RECT 131.800 53.360 132.200 53.760 ;
    END
  END UserCLKo
  PIN VGND
    DIRECTION INOUT ;
    USE GROUND ;
    PORT
      LAYER TopMetal1 ;
        RECT 21.580 0.000 23.780 53.760 ;
    END
    PORT
      LAYER TopMetal1 ;
        RECT 97.180 0.000 99.380 53.760 ;
    END
    PORT
      LAYER TopMetal1 ;
        RECT 172.780 0.000 174.980 53.760 ;
    END
  END VGND
  PIN VPWR
    DIRECTION INOUT ;
    USE POWER ;
    PORT
      LAYER TopMetal1 ;
        RECT 15.380 0.000 17.580 53.760 ;
    END
    PORT
      LAYER TopMetal1 ;
        RECT 90.980 0.000 93.180 53.760 ;
    END
    PORT
      LAYER TopMetal1 ;
        RECT 166.580 0.000 168.780 53.760 ;
    END
  END VPWR
  OBS
      LAYER GatPoly ;
        RECT 2.880 3.630 181.920 49.290 ;
      LAYER Metal1 ;
        RECT 2.880 3.560 181.920 49.360 ;
      LAYER Metal2 ;
        RECT 0.375 53.150 31.750 53.360 ;
        RECT 32.570 53.150 32.710 53.360 ;
        RECT 33.530 53.150 33.670 53.360 ;
        RECT 34.490 53.150 34.630 53.360 ;
        RECT 35.450 53.150 35.590 53.360 ;
        RECT 36.410 53.150 36.550 53.360 ;
        RECT 37.370 53.150 37.510 53.360 ;
        RECT 38.330 53.150 38.470 53.360 ;
        RECT 39.290 53.150 39.430 53.360 ;
        RECT 40.250 53.150 40.390 53.360 ;
        RECT 41.210 53.150 41.350 53.360 ;
        RECT 42.170 53.150 42.310 53.360 ;
        RECT 43.130 53.150 43.270 53.360 ;
        RECT 44.090 53.150 44.230 53.360 ;
        RECT 45.050 53.150 45.190 53.360 ;
        RECT 46.010 53.150 46.150 53.360 ;
        RECT 46.970 53.150 47.110 53.360 ;
        RECT 47.930 53.150 48.070 53.360 ;
        RECT 48.890 53.150 49.030 53.360 ;
        RECT 49.850 53.150 49.990 53.360 ;
        RECT 50.810 53.150 50.950 53.360 ;
        RECT 51.770 53.150 51.910 53.360 ;
        RECT 52.730 53.150 52.870 53.360 ;
        RECT 53.690 53.150 53.830 53.360 ;
        RECT 54.650 53.150 54.790 53.360 ;
        RECT 55.610 53.150 55.750 53.360 ;
        RECT 56.570 53.150 56.710 53.360 ;
        RECT 57.530 53.150 57.670 53.360 ;
        RECT 58.490 53.150 58.630 53.360 ;
        RECT 59.450 53.150 59.590 53.360 ;
        RECT 60.410 53.150 60.550 53.360 ;
        RECT 61.370 53.150 61.510 53.360 ;
        RECT 62.330 53.150 62.470 53.360 ;
        RECT 63.290 53.150 63.430 53.360 ;
        RECT 64.250 53.150 64.390 53.360 ;
        RECT 65.210 53.150 65.350 53.360 ;
        RECT 66.170 53.150 66.310 53.360 ;
        RECT 67.130 53.150 67.270 53.360 ;
        RECT 68.090 53.150 68.230 53.360 ;
        RECT 69.050 53.150 69.190 53.360 ;
        RECT 70.010 53.150 70.150 53.360 ;
        RECT 70.970 53.150 71.110 53.360 ;
        RECT 71.930 53.150 72.070 53.360 ;
        RECT 72.890 53.150 73.030 53.360 ;
        RECT 73.850 53.150 73.990 53.360 ;
        RECT 74.810 53.150 74.950 53.360 ;
        RECT 75.770 53.150 75.910 53.360 ;
        RECT 76.730 53.150 76.870 53.360 ;
        RECT 77.690 53.150 77.830 53.360 ;
        RECT 78.650 53.150 78.790 53.360 ;
        RECT 79.610 53.150 79.750 53.360 ;
        RECT 80.570 53.150 80.710 53.360 ;
        RECT 81.530 53.150 81.670 53.360 ;
        RECT 82.490 53.150 82.630 53.360 ;
        RECT 83.450 53.150 83.590 53.360 ;
        RECT 84.410 53.150 84.550 53.360 ;
        RECT 85.370 53.150 85.510 53.360 ;
        RECT 86.330 53.150 86.470 53.360 ;
        RECT 87.290 53.150 87.430 53.360 ;
        RECT 88.250 53.150 88.390 53.360 ;
        RECT 89.210 53.150 89.350 53.360 ;
        RECT 90.170 53.150 90.310 53.360 ;
        RECT 91.130 53.150 91.270 53.360 ;
        RECT 92.090 53.150 92.230 53.360 ;
        RECT 93.050 53.150 93.190 53.360 ;
        RECT 94.010 53.150 94.150 53.360 ;
        RECT 94.970 53.150 95.110 53.360 ;
        RECT 95.930 53.150 96.070 53.360 ;
        RECT 96.890 53.150 97.030 53.360 ;
        RECT 97.850 53.150 97.990 53.360 ;
        RECT 98.810 53.150 98.950 53.360 ;
        RECT 99.770 53.150 99.910 53.360 ;
        RECT 100.730 53.150 100.870 53.360 ;
        RECT 101.690 53.150 101.830 53.360 ;
        RECT 102.650 53.150 102.790 53.360 ;
        RECT 103.610 53.150 103.750 53.360 ;
        RECT 104.570 53.150 104.710 53.360 ;
        RECT 105.530 53.150 105.670 53.360 ;
        RECT 106.490 53.150 106.630 53.360 ;
        RECT 107.450 53.150 107.590 53.360 ;
        RECT 108.410 53.150 108.550 53.360 ;
        RECT 109.370 53.150 109.510 53.360 ;
        RECT 110.330 53.150 110.470 53.360 ;
        RECT 111.290 53.150 111.430 53.360 ;
        RECT 112.250 53.150 112.390 53.360 ;
        RECT 113.210 53.150 113.350 53.360 ;
        RECT 114.170 53.150 114.310 53.360 ;
        RECT 115.130 53.150 115.270 53.360 ;
        RECT 116.090 53.150 116.230 53.360 ;
        RECT 117.050 53.150 117.190 53.360 ;
        RECT 118.010 53.150 118.150 53.360 ;
        RECT 118.970 53.150 119.110 53.360 ;
        RECT 119.930 53.150 120.070 53.360 ;
        RECT 120.890 53.150 121.030 53.360 ;
        RECT 121.850 53.150 121.990 53.360 ;
        RECT 122.810 53.150 122.950 53.360 ;
        RECT 123.770 53.150 123.910 53.360 ;
        RECT 124.730 53.150 124.870 53.360 ;
        RECT 125.690 53.150 125.830 53.360 ;
        RECT 126.650 53.150 126.790 53.360 ;
        RECT 127.610 53.150 127.750 53.360 ;
        RECT 128.570 53.150 128.710 53.360 ;
        RECT 129.530 53.150 129.670 53.360 ;
        RECT 130.490 53.150 130.630 53.360 ;
        RECT 131.450 53.150 131.590 53.360 ;
        RECT 132.410 53.150 132.550 53.360 ;
        RECT 133.370 53.150 133.510 53.360 ;
        RECT 134.330 53.150 134.470 53.360 ;
        RECT 135.290 53.150 135.430 53.360 ;
        RECT 136.250 53.150 136.390 53.360 ;
        RECT 137.210 53.150 137.350 53.360 ;
        RECT 138.170 53.150 138.310 53.360 ;
        RECT 139.130 53.150 139.270 53.360 ;
        RECT 140.090 53.150 140.230 53.360 ;
        RECT 141.050 53.150 141.190 53.360 ;
        RECT 142.010 53.150 142.150 53.360 ;
        RECT 142.970 53.150 143.110 53.360 ;
        RECT 143.930 53.150 144.070 53.360 ;
        RECT 144.890 53.150 145.030 53.360 ;
        RECT 145.850 53.150 145.990 53.360 ;
        RECT 146.810 53.150 146.950 53.360 ;
        RECT 147.770 53.150 147.910 53.360 ;
        RECT 148.730 53.150 148.870 53.360 ;
        RECT 149.690 53.150 149.830 53.360 ;
        RECT 150.650 53.150 150.790 53.360 ;
        RECT 151.610 53.150 184.425 53.360 ;
        RECT 0.375 0.610 184.425 53.150 ;
        RECT 0.375 0.100 4.870 0.610 ;
        RECT 5.690 0.100 13.510 0.610 ;
        RECT 14.330 0.100 22.150 0.610 ;
        RECT 22.970 0.100 30.790 0.610 ;
        RECT 31.610 0.100 39.430 0.610 ;
        RECT 40.250 0.100 48.070 0.610 ;
        RECT 48.890 0.100 56.710 0.610 ;
        RECT 57.530 0.100 65.350 0.610 ;
        RECT 66.170 0.100 73.990 0.610 ;
        RECT 74.810 0.100 82.630 0.610 ;
        RECT 83.450 0.100 91.270 0.610 ;
        RECT 92.090 0.100 99.910 0.610 ;
        RECT 100.730 0.100 108.550 0.610 ;
        RECT 109.370 0.100 117.190 0.610 ;
        RECT 118.010 0.100 125.830 0.610 ;
        RECT 126.650 0.100 134.470 0.610 ;
        RECT 135.290 0.100 143.110 0.610 ;
        RECT 143.930 0.100 151.750 0.610 ;
        RECT 152.570 0.100 160.390 0.610 ;
        RECT 161.210 0.100 169.030 0.610 ;
        RECT 169.850 0.100 177.670 0.610 ;
        RECT 178.490 0.100 184.425 0.610 ;
      LAYER Metal3 ;
        RECT 0.335 52.910 184.465 53.445 ;
        RECT 0.610 52.090 184.190 52.910 ;
        RECT 0.335 51.230 184.465 52.090 ;
        RECT 0.610 50.410 184.190 51.230 ;
        RECT 0.335 49.550 184.465 50.410 ;
        RECT 0.610 48.730 184.190 49.550 ;
        RECT 0.335 47.870 184.465 48.730 ;
        RECT 0.610 47.050 184.190 47.870 ;
        RECT 0.335 46.190 184.465 47.050 ;
        RECT 0.610 45.370 184.190 46.190 ;
        RECT 0.335 44.510 184.465 45.370 ;
        RECT 0.610 43.690 184.190 44.510 ;
        RECT 0.335 42.830 184.465 43.690 ;
        RECT 0.610 42.010 184.190 42.830 ;
        RECT 0.335 41.150 184.465 42.010 ;
        RECT 0.610 40.330 184.190 41.150 ;
        RECT 0.335 39.470 184.465 40.330 ;
        RECT 0.610 38.650 184.190 39.470 ;
        RECT 0.335 37.790 184.465 38.650 ;
        RECT 0.610 36.970 184.190 37.790 ;
        RECT 0.335 36.110 184.465 36.970 ;
        RECT 0.610 35.290 184.190 36.110 ;
        RECT 0.335 34.430 184.465 35.290 ;
        RECT 0.610 33.610 184.190 34.430 ;
        RECT 0.335 32.750 184.465 33.610 ;
        RECT 0.610 31.930 184.190 32.750 ;
        RECT 0.335 31.070 184.465 31.930 ;
        RECT 0.610 30.250 184.190 31.070 ;
        RECT 0.335 29.390 184.465 30.250 ;
        RECT 0.610 28.570 184.190 29.390 ;
        RECT 0.335 27.710 184.465 28.570 ;
        RECT 0.610 26.890 184.190 27.710 ;
        RECT 0.335 26.030 184.465 26.890 ;
        RECT 0.610 25.210 184.190 26.030 ;
        RECT 0.335 24.350 184.465 25.210 ;
        RECT 0.610 23.530 184.190 24.350 ;
        RECT 0.335 22.670 184.465 23.530 ;
        RECT 0.610 21.850 184.190 22.670 ;
        RECT 0.335 20.990 184.465 21.850 ;
        RECT 0.610 20.170 184.190 20.990 ;
        RECT 0.335 19.310 184.465 20.170 ;
        RECT 0.610 18.490 184.190 19.310 ;
        RECT 0.335 17.630 184.465 18.490 ;
        RECT 0.610 16.810 184.190 17.630 ;
        RECT 0.335 15.950 184.465 16.810 ;
        RECT 0.610 15.130 184.190 15.950 ;
        RECT 0.335 14.270 184.465 15.130 ;
        RECT 0.610 13.450 184.190 14.270 ;
        RECT 0.335 12.590 184.465 13.450 ;
        RECT 0.610 11.770 184.190 12.590 ;
        RECT 0.335 10.910 184.465 11.770 ;
        RECT 0.610 10.090 184.190 10.910 ;
        RECT 0.335 9.230 184.465 10.090 ;
        RECT 0.610 8.410 184.190 9.230 ;
        RECT 0.335 7.550 184.465 8.410 ;
        RECT 0.610 6.730 184.190 7.550 ;
        RECT 0.335 5.870 184.465 6.730 ;
        RECT 0.610 5.050 184.190 5.870 ;
        RECT 0.335 4.190 184.465 5.050 ;
        RECT 0.610 3.370 184.190 4.190 ;
        RECT 0.335 2.510 184.465 3.370 ;
        RECT 0.610 1.690 184.190 2.510 ;
        RECT 0.335 0.830 184.465 1.690 ;
        RECT 0.610 0.320 184.190 0.830 ;
      LAYER Metal4 ;
        RECT 0.375 3.635 180.585 53.485 ;
      LAYER Metal5 ;
        RECT 0.335 3.470 180.625 53.440 ;
  END
END S_term_DSP
END LIBRARY

